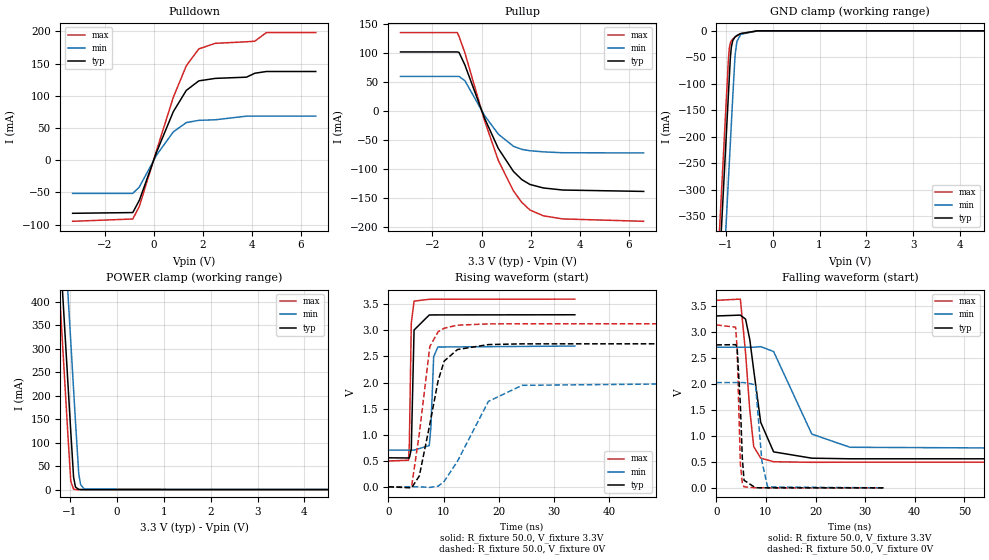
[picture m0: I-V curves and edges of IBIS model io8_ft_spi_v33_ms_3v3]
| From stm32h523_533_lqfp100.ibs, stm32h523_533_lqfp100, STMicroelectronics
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[Model]   io8_ft_spi_v33_ms_3v3
Model_type I/O
Polarity   Non-Inverting
Enable   Active-Low
| CAP_THRESHOLD on pad IOFT is "UDTCAPC" :
| Rising=20.0% of vddiom   Falling=80.0% of vddiom
| C_comp min and max val. don't necessarily correlate with the min and max pvt
| but are the smallest and greatest pad capacitance found.
| var   typ   min   max
C_comp   3.95307pF  3.95030pF  4.00772pF
|C_comp_pullup   2.45805pF  2.54065pF  2.38980pF
|C_comp_pulldown   1.49502pF  1.40965pF  1.61792pF
Vinl = 810.0mV
Vinh = 2.52V
Vmeas = 1.65V   | Reference voltage for timing measurements
Cref  = 50.0pF   | Timing specification test load capacitance value
Rref  = 100.0MOhm   | Timing specification test load resistance value
Vref  = 1.65V   | Timing specification test load voltage
[Model Spec]
| TIME_THRESHOLD on pin ZIV33M is "CMOS" :
| Rising=40.0% of vddiom   Falling=60.0% of vddiom
Vinl 1.28680V 1.06380V 1.39380V
Vinh 1.76920V 1.48820V 1.89120V
| variable   typ   min   max
[Temperature Range] 25.0 125.0 -40.0
| variable   typ   min   max
[Voltage Range] 3.3V 2.7V 3.6V
| variable   typ   min   max
[POWER Clamp Reference] 3.3V 2.7V 3.6V
| variable   typ   min   max
[GND Clamp Reference] 0V 0V 0V
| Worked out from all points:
|   slope of the pulldown table from 0 to 0.495 V, typ, clamps not added: 10 ohm
|   slope of the pullup table from 0 to 0.495 V, typ, clamps not added: 10 ohm
|   GND clamp passes 1 mA (typ) near -0.52 V on its own axis
|   POWER clamp passes 1 mA (typ) near -0.84 V on its own axis
|   rising waveform, R_fixture 50.0, V_fixture 3.3V: 20-80 % time 292ps typ, 395ps min, 268ps max; typ from 0.556 V to 3.3 V
|   falling waveform, R_fixture 50.0, V_fixture 3.3V: 20-80 % time 2.77ns typ, 5.34ns min, 1.51ns max; typ from 3.3 V to 0.556 V
|   rising waveform, R_fixture 50.0, V_fixture 0V: 20-80 % time 2.98ns typ, 5.89ns min, 2ns max; typ from 0 V to 2.74 V
|   falling waveform, R_fixture 50.0, V_fixture 0V: 20-80 % time 655ps typ, 985ps min, 526ps max; typ from 2.74 V to 0 V
[POWER Clamp]
-3.3V     4.068A     4.259A     3.957A
-1.25V    582.8mA    774.2mA    471.5mA
-1.21V    514.8mA    706.2mA    403.5mA
-1.13V    378.8mA    570.2mA    267.5mA
-1.04V    225.8mA    417.2mA    114.5mA
-980mV    123.8mA    315.2mA    17.95mA
-920mV    26.3mA     213.2mA    906uA
-880mV    5.543mA    145.2mA    123.7uA
-810mV    363.5uA    33.6mA     3.798uA
-770mV    76.62uA    10.47mA    519.4nA
-690mV    3.409uA    1.017mA    10.47nA
6.6V      0A         0A         0A
[GND Clamp]
-3.3V     -4.13A     -4.291A    -4.063A
-1.25V    -644.7mA   -806.4mA   -578.1mA
-940mV    -117.7mA   -279.4mA   -51.06mA
-920mV    -83.75mA   -245.4mA   -31.43mA
-900mV    -50.5mA    -211.4mA   -23.14mA
-880mV    -31.27mA   -177.4mA   -19.1mA
-850mV    -18.68mA   -126.4mA   -15.73mA
-800mV    -11.46mA   -46.4mA    -12.03mA
-760mV    -8.752mA   -20.02mA   -9.606mA
-680mV    -5.122mA   -6.673mA   -5.579mA
-320mV    -10.25uA   -73.91uA   -1.981uA
6.6V      10.49nA    1.843uA    393.6pA
| variable   typ   min   max
[Pullup Reference] 3.3V 2.7V 3.6V
| variable   typ   min   max
[Pulldown Reference] 0V 0V 0V
[Pullup]
-3.3V     101.1mA    58.92mA    134.5mA
-990mV    101.1mA    58.92mA    134.5mA
-920mV    100.4mA    58.92mA    128.1mA
-680mV    78.71mA    51.62mA    99.66mA
120mV     -12.97mA   -8.371mA   -17mA
680mV     -65.16mA   -40.47mA   -85.72mA
1.3V      -105mA     -61.59mA   -138.6mA
1.64V     -119mA     -66.82mA   -158.3mA
1.97V     -127.3mA   -69.18mA   -171.3mA
2.51V     -133.3mA   -71.08mA   -181.3mA
3.3V      -136.9mA   -72.64mA   -186.7mA
6.6V      -139.3mA   -72.98mA   -190.8mA
[Pulldown]
-3.3V     -82.42mA   -51.49mA   -94.82mA
-850mV    -81.27mA   -51.49mA   -91.26mA
-580mV    -62.01mA   -41.36mA   -71.41mA
120mV     12.61mA    7.999mA    15.37mA
800mV     75.3mA     43.94mA    97.52mA
1.33V     108.3mA    58.37mA    146.5mA
1.84V     123.1mA    61.83mA    172.7mA
2.51V     126.9mA    62.7mA     181.3mA
3.78V     128.8mA    68.32mA    183.7mA
4.12V     134.9mA    68.32mA    184.6mA
4.59V     137.6mA    68.32mA    198mA
6.6V      137.6mA    68.32mA    198mA
[Ramp]
dV/dt_r 1.64651V/2.97557ns 1.21265V/5.86801ns 1.87653V/1.99932ns
dV/dt_f 1.64666V/2.32716ns 1.19801V/5.11841ns 1.86387V/1.50423ns
R_load = 50.0
| Removed startup time: 0s 0s 0s  .
| Removed end time: 33.75ns.
[Rising Waveform]
R_fixture   = 50.0
V_fixture   = 3.3V
V_fixture_min = 2.7V
V_fixture_max = 3.6V
0s        555.6mV    703.3mV    493.6mV
3.65ns    552.4mV    703.3mV    510.2mV
3.8ns     552.5mV    703.3mV    832.4mV
4.15ns    723mV      703.3mV    3.139V
4.65ns    3.007V     703.3mV    3.562V
7.4ns     3.296V     790.7mV    3.597V
7.7ns     3.296V     1.143V     3.597V
8.2ns     3.297V     2.497V     3.598V
8.95ns    3.297V     2.681V     3.598V
33.75ns   3.3V       2.7V       3.6V
| Removed startup time: 0s 0s 0s  .
| Removed end time: 188.75ns.
[Falling Waveform]
R_fixture   = 50.0
V_fixture   = 3.3V
V_fixture_min = 2.7V
V_fixture_max = 3.6V
0s        3.3V       2.7V       3.6V
4.85ns    3.316V     2.7V       3.623V
5.9ns     3.239V     2.7V       2.591V
6.75ns    2.847V     2.7V       1.493V
7.55ns    2.254V     2.7V       791.2mV
8.95ns    1.259V     2.711V     571.6mV
11.55ns   691mV      2.617V     501.4mV
19.25ns   569.7mV    1.032V     490.3mV
26.95ns   558.2mV    779.2mV    493mV
188.8ns   555.6mV    703.3mV    493.6mV
| Removed startup time: 0s 0s 0s  .
| Removed end time: 98.6ns.
[Rising Waveform]
R_fixture   = 50.0
V_fixture   = 0V
V_fixture_min = 0V
V_fixture_max = 0V
0s        228.2nV    417.4nV    212.7nV
4.2ns     -20.93mV   432.4nV    1.293mV
5.6ns     207.5mV    -297.7nV   1.019V
7.5ns     1.198V     -12.88mV   2.69V
9ns       2.034V     11mV       2.974V
10.1ns    2.411V     102.9mV    3.042V
12.5ns    2.633V     488.9mV    3.1V
18.1ns    2.728V     1.638V     3.125V
24.2ns    2.742V     1.946V     3.127V
98.6ns    2.744V     2.021V     3.128V
| Removed startup time: 0s 0s 0s  .
| Removed end time: 33.7ns.
[Falling Waveform]
R_fixture   = 50.0
V_fixture   = 0V
V_fixture_min = 0V
V_fixture_max = 0V
0s        2.744V     2.021V     3.128V
3.9ns     2.749V     2.021V     3.084V
4.2ns     2.699V     2.021V     2.673V
4.85ns    1.604V     2.021V     461.6mV
5.25ns    564.2mV    2.021V     87.69mV
5.6ns     144.8mV    2.021V     19.56mV
7.9ns     2.821mV    1.978V     1.496mV
9.2ns     1.625mV    508.4mV    1.01mV
10.35ns   1.169mV    17.17mV    777.9uV
33.7ns    17.42uV    160uV      3.837uV
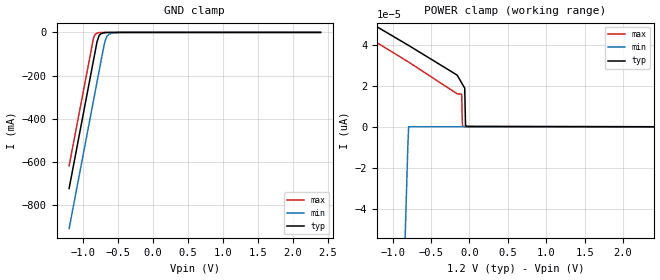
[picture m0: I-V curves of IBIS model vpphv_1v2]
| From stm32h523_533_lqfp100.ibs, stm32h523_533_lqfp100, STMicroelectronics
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[Model]   vpphv_1v2
Model_type Input
Polarity   Non-Inverting
Enable   Active-Low
| CAP_THRESHOLD on pad VPPHV is "UDTCAPC" :
| Rising=20.0% of vddiom   Falling=80.0% of vddiom
| C_comp min and max val. don't necessarily correlate with the min and max pvt
| but are the smallest and greatest pad capacitance found.
| var   typ   min   max
C_comp   1.79994pF  1.79070pF  1.91534pF
|C_comp_pullup   569.84000fF  588.29500fF  599.59000fF
|C_comp_pulldown   1.23010pF  1.20240pF  1.31575pF
Vinl = 270.0mV
Vinh = 924.0mV
[Model Spec]
| TIME_THRESHOLD on pin ZIV11 is "CMOS" :
| Rising=40.0% of vdd   Falling=60.0% of vdd
Vinl 379.80000mV 297.80000mV 412.80000mV
Vinh 683.20000mV 554.20000mV 725.20000mV
| variable   typ   min   max
[Temperature Range] 25.0 125.0 -40.0
| variable   typ   min   max
[Voltage Range] 1.2V 900.0mV 1.32V
| variable   typ   min   max
[POWER Clamp Reference] 1.2V 900.0mV 1.32V
| variable   typ   min   max
[GND Clamp Reference] 0V 0V 0V
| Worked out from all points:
|   GND clamp passes 1 mA (typ) near -0.68 V on its own axis
[POWER Clamp]
-1.2V     48.59pA    -512.5pA   40.85pA
-820mV    40.21pA    -34pA      32.14pA
-800mV    39.76pA    -9pA       31.67pA
-790mV    39.55pA    0A         31.46pA
-160mV    25.15pA    0A         16.05pA
-100mV    21.35pA    0A         15.83pA
-90mV     20.68pA    0A         208fA
-60mV     18.77pA    0A         71fA
-50mV     597fA      0A         51fA
-30mV     180fA      0A         36fA
2.4V      0A         0A         0A
[GND Clamp]
-1.2V     -723.1mA   -909.2mA   -618.6mA
-850mV    -128.1mA   -314.2mA   -25.36mA
-830mV    -94.06mA   -280.2mA   -10.28mA
-800mV    -43.06mA   -229.2mA   -3.086mA
-770mV    -14.35mA   -178.2mA   -1.145mA
-740mV    -5.154mA   -127.2mA   -473.3uA
-690mV    -1.177mA   -44.65mA   -117.3uA
-660mV    -527.4uA   -19.49mA   -62.86uA
-630mV    -230.5uA   -8.819mA   -39.58uA
-570mV    -42.05uA   -2.133mA   -17.18uA
-430mV    -1.506uA   -104.9uA   -645.6nA
2.4V      187.6pA    5.869nA    154.2pA
